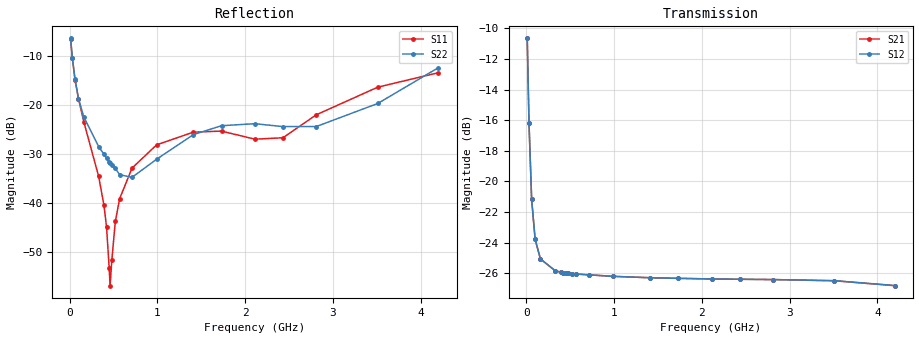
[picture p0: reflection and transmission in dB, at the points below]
! Integrated Device Technology
! Corporate Headquarters
! 6024 Silver Creek Valley Road
! San Jose, CA 95138  USA
! Phone:  1-408-284-8200
! Toll Free:  1-800-223-1366
! Webpage:  http://www.idt.com/
! Timing and RF Division
! 515 Groton Road, Suite 102
! Westford, MA 01886-6024
! Device:  F1950
! Description: 7-bit 0.25 dB Digital Step Attenuator
! Frequency:  150.0 -  4000.00 MHz
! Package:  4x4 mm Thin QFN Plastic Package: 24 pin
! Ports:  2 RF, 12 DC
!  Pin  1  = D0
!  Pin  2  = VDD
!  Pin  3  = Vmode
!  Pin  4  = GND
!  Pin  5  = RF1  =  Port 1
!  Pin  6  = GND
!  Pin  7  = GND
!  Pin  8  = GND
!  Pin  9  = GND
!  Pin 10  = GND
!  Pin 11  = GND
!  Pin 12  = GND
!  Pin 13  = GND
!  Pin 14  = RF2  =  Port 2
!  Pin 15  = GND
!  Pin 16  = LE
!  Pin 17  = CLK
!  Pin 18  = DATE
!  Pin 19  = D6
!  Pin 20  = D5
!  Pin 21  = D4
!  Pin 22  = D3
!  Pin 23  = D2
!  Pin 24  = D1
! State:  101
! Atten State:  25.25 dB
! Voltage:  +5.00 Volts
! Current:  Not Measured mA
! Data:  The device was measured on a the F195X evaluation board which has
!  individual transmission lines to the RF pins.  Data was collected
!  using a calibrated network analyzer.  The evaluation board was
!  de-embedded using a TRL calibration technique.
!  The reference plane is the edge of the package pin.
! Misc:  Board 2019
!  Action Tracker AT0250
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# GHz S dB R 50
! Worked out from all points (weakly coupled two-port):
!   420 points, 10 MHz to 4.2 GHz, reference 50 ohm
!   highest |S21| = -10.65 dB at 10 MHz (marker M1); lowest = -26.8 dB at 4.2 GHz (marker M2)
!   lowest |S11| = -57.0 dB at 460 MHz (marker M3), VSWR 1.00, Z = 49.9 - j0.0948 ohm
!   |S11| at or under -10 dB: 27.58 MHz to end of sweep
!   |S22| runs from -35.1 to -6.5 dB; largest |S21 - S12| = 0.00011
!   S11 on the Smith chart (normalised r, x): 10 MHz: 2.07, -1.10; 30 MHz: 1.29, -0.65; 60 MHz: 1.11, -0.37; 390 MHz: 1.01, -0.02; 4.2 GHz: 0.69, +0.17
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0.01  -6.54 -26.0  -10.65 -32.6  -10.65 -32.6  -6.47 -26.9
0.03  -10.46 -50.2  -16.19 -52.5  -16.19 -52.5  -10.39 -51.6
0.06  -14.91 -63.5  -21.18 -48.8  -21.18 -48.8  -14.69 -65.0
0.1  -18.80 -70.2  -23.79 -37.5  -23.79 -37.5  -18.77 -70.5
0.16  -23.46 -72.0  -25.07 -27.1  -25.07 -27.0  -22.50 -75.5
0.33  -34.66 -70.4  -25.85 -16.9  -25.85 -16.9  -28.57 -83.8
0.39  -40.51 -70.4  -25.93 -15.7  -25.93 -15.7  -30.13 -86.2
0.42  -45.01 -78.0  -25.96 -15.3  -25.96 -15.3  -30.99 -88.2
0.45  -53.39 -102.8  -25.99 -14.9  -25.99 -14.9  -31.74 -92.7
0.46  -56.98 -137.9  -26.00 -14.9  -26.00 -14.9  -31.94 -94.4
0.48  -51.81 153.0  -26.01 -14.7  -26.01 -14.7  -32.25 -97.2
0.52  -43.80 139.3  -26.03 -14.5  -26.03 -14.5  -33.04 -100.6
0.57  -39.18 134.3  -26.06 -14.3  -26.06 -14.3  -34.32 -110.2
0.71  -32.97 137.6  -26.11 -14.4  -26.11 -14.4  -34.86 -138.1
0.99  -28.22 147.2  -26.21 -15.8  -26.21 -15.8  -31.16 -179.4
1.41  -25.62 162.9  -26.30 -18.8  -26.30 -18.8  -26.12 160.7
1.73  -25.41 168.2  -26.34 -21.4  -26.34 -21.4  -24.31 152.2
2.11  -27.06 157.7  -26.38 -25.1  -26.38 -25.1  -23.90 142.3
2.43  -26.77 126.0  -26.40 -27.9  -26.40 -27.9  -24.49 131.6
2.81  -22.08 105.1  -26.42 -31.8  -26.42 -31.8  -24.48 116.2
3.51  -16.44 117.3  -26.50 -38.6  -26.49 -38.6  -19.77 113.3
4.2  -13.49 145.5  -26.82 -43.1  -26.81 -43.2  -12.47 127.2
